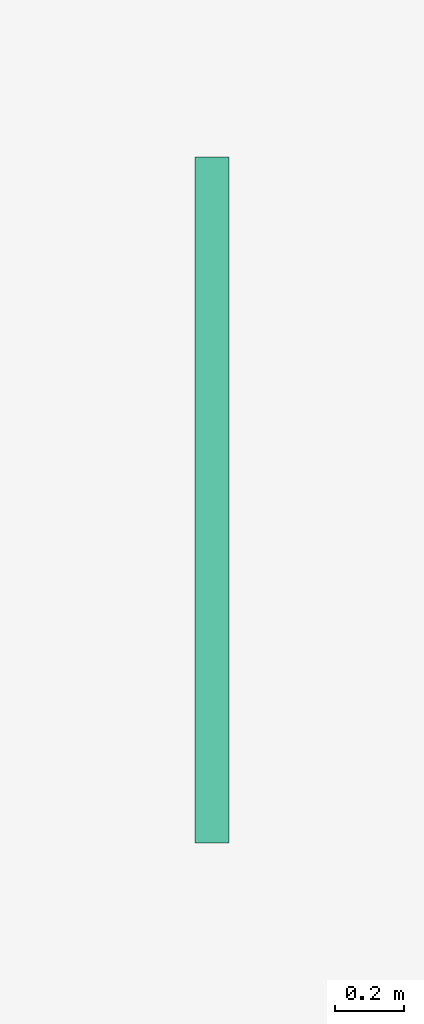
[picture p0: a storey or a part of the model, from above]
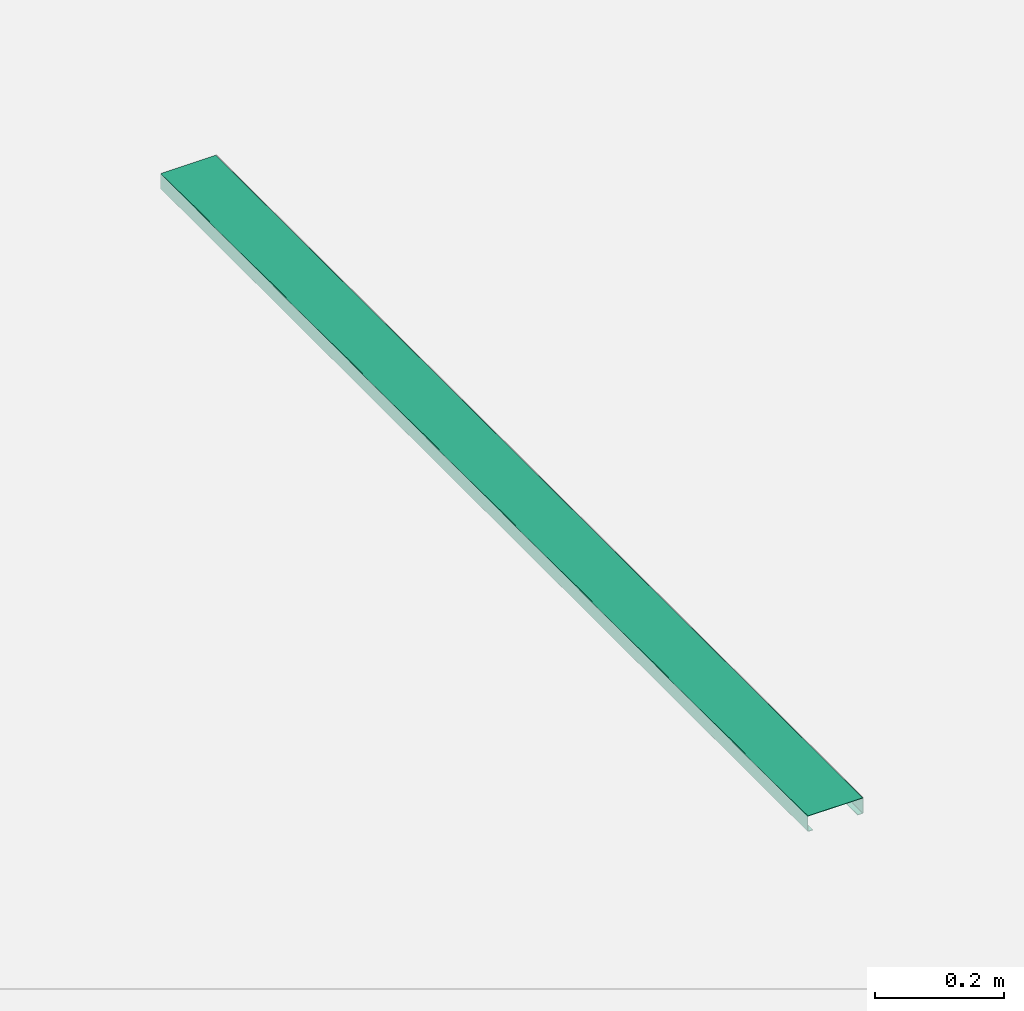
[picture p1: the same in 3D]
Properties of the parts of a building model (IFC2X3)

# File
Description: ViewDefinition [CoordinationView]
File name: Project Number
Time: 2014-06-06T11:11:41
Written by: The EXPRESS Data Manager Version 5.01.0100.02.64mod : 6 Jun 2012
Made in: 20130308_1515(x64) - Exporter 2014.0.2013.0308 - Default UI
Comment: STEP Physical File produced by: The EXPRESS Data Manager Version 5.01.0100.02.64mod : 6 Jun 2012 * Module: EDMstepFileFactory/EDMstandAlone * Creation date: Fri Jun 06 11:11:41 2014 * Host: IN-BLR-PC-0010 * Database: C:\Users\palleri\AppData\Local\Temp\{8C0645B5-5B0F-4C37-B3CA-A9FBCA849082}\ifc * Database version: 5507 * Database creation date: Fri Jun 06 11:11:41 2014 * Schema: IFC2X3 * Model: DataRepository.ifc * Model creation date: Fri Jun 06 11:11:41 2014 * Header model: DataRepository.ifc_HeaderModel * Header model creation date: Fri Jun 06 11:11:41 2014 * EDMuser: sdai-user * EDMgroup: sdai-group * License ID and type: 5605 : Permanent license. Expiry date: * EDMstepFileFactory options: 020000

# IfcProject, Project Number
LongName: Project Name; Phase: Project Status

# IfcSite, Default
RefLatitude: 42, 21, 30, 344238; RefLongitude: -71, -3, -35, -194702; RefElevation: 0 mm

# IfcBuilding
Pset_BuildingCommon - NumberOfStoreys: 1
Other - Project Name: Project Name; Project Address: ## Street City, State Zip; Project Number: Project Number; Client Name: Owner; Project Status: Project Status; Project Issue Date: Issue Date

# IfcBuildingStorey, Level 1
LongName: Level 1; Elevation: 0 mm
Constraints - Elevation Base: Project Base Point; Elevation: 0 mm
Graphics - Line Pattern: Center; Line Weight: 1; Symbol at End 1 Default: no; Symbol at End 2 Default: yes; Color: 0; Symbol: M_Level Head - Circle: M_Level Head - Circle
Identity Data - Building Story: yes; Structural: no; Name: Level 1
Dimensions - Computation Height: 0 mm

# IfcFlowTerminal: 00307 - Drainage Duct - 2000mm LG, ACO Freedeck Access Frame & Drain Duct (Accessories part 1) V1.27 - SS:00307 - Drainage Duct - 2000mm LG:278221
In: Level 1
Material: Stainless Steel Grade 304
Other - Access Frame Extension: yes; Access Frame Extension_Invert Depth 75mm: yes; Drain Duct Vertical Height: 30 mm; Access Frame Extension Height: 75 mm; Fixed Access Frame Position Height: 105 mm; Extension Removal Void: 400 mm; Access Frame Extension_Invert Depth 50mm: no; Adjustable Access Frame Position Height: 105 mm; Grating: no; Access Frame Adjustable Height: no; Top void Size: 397 mm; Drain Duct: yes; Access Frame Fixed Height: no
Phasing - Phase Created: New Construction
Dimensions - Top Void Height End: 0 mm; Access Frame Extension Position Height: 5000 mm; Total Height: 159 mm; Height for Adjustable Access Frame: 105 mm; Base Height: 3000 mm; Drainage Duct – Level below FFL: 30 mm; Top Void Height Start: 2 mm; Grating End: -20 mm; Grating Start: 0 mm; Drain Duct End: -2000 mm
Constraints - Level: Level: Level 1; Moves With Nearby Elements: no
Construction - 36760_Access Grating_Mesh Grating_Stainless Steel 304: no; 38688_Access Frame Extension_Stainless Steel_Invert Depth 75mm: yes; 38686_Access Frame Extension_Stainless Steel_Invert Depth 50mm: no
Identity Data - Mark: 15; Watermark2: This file is water marked and users are prohibited to reproduce, adapt, distribute this information; E-mail Sales: abdcommercial@aco.co.uk; Watermark1: This file is the property of ACO Technologies PLC; Address: ACO Business Centre, Caxton Road, Bedford, MK41 0LF; E-mail Technical: abdtechnical@aco.co.uk; Manufacturer: ACO Building Drainage; Watermarked By: www.acobd.com; Telephone: +44 (0)1462 816666; Watermarked With: BIM Manager Premium Suite; Website: www.acobd.com; Fax: +44 (0)1462 851490
Pset_ManufacturerTypeInformation - Manufacturer: ACO Building Drainage
General - Product Type: Linear Deck Drainage System; Product Standard: BS EN 1433:2002, CE marked; Channel Recycled Material Content: 60 - 70 %; Channel Material: Stainless Steel Grade 304; Load Class: A15; Product Code: 00307; Product Range: ACO Freedeck; Price: POA - contact ACO; Weight (Kg): 2.4kg; Channel Colour: Mid Grey; Dimensions (LxWxH): 100 x 30 x 2000; Channel Recyclable: Fully recyclable; Installation Guidelines: X:\Electronic Literature\ABD Electronic Literature\Roof and Balcony Drainage\ACO Freedeck Brochure.pdf; Maintenance Guidelines: X:\Electronic Literature\ABD Electronic Literature\Roof and Balcony Drainage\ACO Freedeck Brochure.pdf; Product Description: ACO Freedeck Drainage Duct; NBS Specification: NBS Section R10 Gravity Rainwater Drainage Systems, Subsection 365
Model Properties - Access Frame Extension Product Code 38688: Load Class A15 - Access Frame Extension - Stainless Steel 304 - Invert Depth 75mm - 1.9kg; Access Grating Product Code 36754: N/A; Access Frame Extension Product Code 38686: Load Class A15 - Access Frame Extension - Stainless Steel 304 - Invert Depth 50mm - 1.3kg; Access Frame Extension Product Code 38687: N/A; Access Grating Product Code 36760: Load Class A15 - Mesh Grating - 14mm x 30mm Mesh - Stainless Steel 304 - 3.5kg; Access Frame Extension Product Code 38685: N/A
Materials and Finishes - Material: Stainless Steel Grade 304

# IfcSlab: Floor:Generic Floor - 400mm, Floor:Generic Floor - 400mm:193825
In: Level 1
PredefinedType: FLOOR; Material: Concrete, Broom Finish 400 mm
Phasing - Phase Created: New Construction
Dimensions - Volume: 6.394 m3; Thickness: 400 mm; Perimeter: 16000 mm; Area: 16 m2
Structural - Structural: no; Enable Analytical Model: no
Constraints - Level: Level: Level 1; Height Offset From Level: 0 mm; Room Bounding: yes; Related to Mass: no
Pset_SlabCommon - Reference: Generic Floor - 400mm; IsExternal: no; LoadBearing: yes; ThermalTransmittance: 2.615 kg/K/s3; PitchAngle: 0 deg
Construction - Function: Interior; Default Thickness: 400 mm
Analytical Properties - Thermal Resistance (R): 0.382409; Heat Transfer Coefficient (U): 2.615; Thermal mass: 604440; Absorptance: 0.1; Roughness: 1
Materials and Finishes - Structural Material: Concrete, Broom Finish
Graphics - Coarse Scale Fill Color: 0
